One B-rep face of a CAD part: STEP entity #1081.
In plain terms, the planar face has unit normal (0, -1, 0).
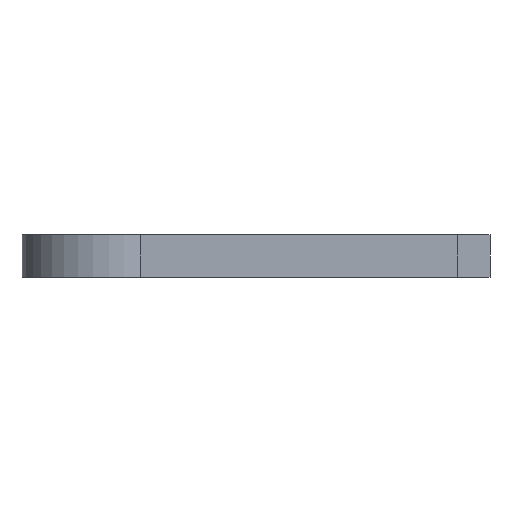
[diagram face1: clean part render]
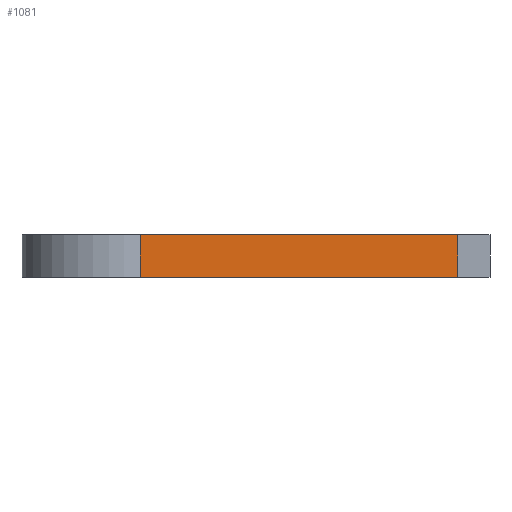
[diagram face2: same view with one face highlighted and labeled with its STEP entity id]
Its self-contained STEP definition (entity closure, numbers rounded to 3 decimals):
#42 = VERTEX_POINT('',#43);
#43 = CARTESIAN_POINT('',(65.8,-85.5,9.6));
#50 = PLANE('',#51);
#51 = AXIS2_PLACEMENT_3D('',#52,#53,#54);
#52 = CARTESIAN_POINT('',(65.8,-100.2,4.8));
#53 = DIRECTION('',(1.,0.,0.));
#54 = DIRECTION('',(0.,0.,1.));
#62 = PLANE('',#63);
#63 = AXIS2_PLACEMENT_3D('',#64,#65,#66);
#64 = CARTESIAN_POINT('',(65.8,-100.2,9.6));
#65 = DIRECTION('',(0.,0.,1.));
#66 = DIRECTION('',(1.,0.,-0.));
#272 = VERTEX_POINT('',#273);
#273 = CARTESIAN_POINT('',(65.8,-85.5,57.292));
#288 = CYLINDRICAL_SURFACE('',#289,14.);
#289 = AXIS2_PLACEMENT_3D('',#290,#291,#292);
#290 = CARTESIAN_POINT('',(65.8,-72.,61.));
#291 = DIRECTION('',(1.,0.,0.));
#292 = DIRECTION('',(0.,0.,-1.));
#300 = EDGE_CURVE('',#42,#272,#301,.T.);
#301 = SURFACE_CURVE('',#302,(#306,#313),.PCURVE_S1.);
#302 = LINE('',#303,#304);
#303 = CARTESIAN_POINT('',(65.8,-85.5,9.6));
#304 = VECTOR('',#305,1.);
#305 = DIRECTION('',(0.,0.,1.));
#306 = PCURVE('',#50,#307);
#307 = DEFINITIONAL_REPRESENTATION('',(#308),#312);
#308 = LINE('',#309,#310);
#309 = CARTESIAN_POINT('',(4.8,-14.7));
#310 = VECTOR('',#311,1.);
#311 = DIRECTION('',(1.,0.));
#312 = ( GEOMETRIC_REPRESENTATION_CONTEXT(2) 
PARAMETRIC_REPRESENTATION_CONTEXT() REPRESENTATION_CONTEXT('2D SPACE',''
  ) );
#313 = PCURVE('',#314,#319);
#314 = PLANE('',#315);
#315 = AXIS2_PLACEMENT_3D('',#316,#317,#318);
#316 = CARTESIAN_POINT('',(65.8,-85.5,9.6));
#317 = DIRECTION('',(0.,1.,0.));
#318 = DIRECTION('',(0.,-0.,1.));
#319 = DEFINITIONAL_REPRESENTATION('',(#320),#324);
#320 = LINE('',#321,#322);
#321 = CARTESIAN_POINT('',(0.,0.));
#322 = VECTOR('',#323,1.);
#323 = DIRECTION('',(1.,0.));
#324 = ( GEOMETRIC_REPRESENTATION_CONTEXT(2) 
PARAMETRIC_REPRESENTATION_CONTEXT() REPRESENTATION_CONTEXT('2D SPACE',''
  ) );
#530 = VERTEX_POINT('',#531);
#531 = CARTESIAN_POINT('',(72.2,-85.5,9.6));
#545 = PLANE('',#546);
#546 = AXIS2_PLACEMENT_3D('',#547,#548,#549);
#547 = CARTESIAN_POINT('',(72.2,-100.2,4.8));
#548 = DIRECTION('',(1.,0.,0.));
#549 = DIRECTION('',(0.,0.,1.));
#557 = EDGE_CURVE('',#42,#530,#558,.T.);
#558 = SURFACE_CURVE('',#559,(#563,#570),.PCURVE_S1.);
#559 = LINE('',#560,#561);
#560 = CARTESIAN_POINT('',(65.8,-85.5,9.6));
#561 = VECTOR('',#562,1.);
#562 = DIRECTION('',(1.,0.,0.));
#563 = PCURVE('',#62,#564);
#564 = DEFINITIONAL_REPRESENTATION('',(#565),#569);
#565 = LINE('',#566,#567);
#566 = CARTESIAN_POINT('',(0.,14.7));
#567 = VECTOR('',#568,1.);
#568 = DIRECTION('',(1.,0.));
#569 = ( GEOMETRIC_REPRESENTATION_CONTEXT(2) 
PARAMETRIC_REPRESENTATION_CONTEXT() REPRESENTATION_CONTEXT('2D SPACE',''
  ) );
#570 = PCURVE('',#314,#571);
#571 = DEFINITIONAL_REPRESENTATION('',(#572),#576);
#572 = LINE('',#573,#574);
#573 = CARTESIAN_POINT('',(0.,0.));
#574 = VECTOR('',#575,1.);
#575 = DIRECTION('',(0.,1.));
#576 = ( GEOMETRIC_REPRESENTATION_CONTEXT(2) 
PARAMETRIC_REPRESENTATION_CONTEXT() REPRESENTATION_CONTEXT('2D SPACE',''
  ) );
#1037 = VERTEX_POINT('',#1038);
#1038 = CARTESIAN_POINT('',(72.2,-85.5,57.292));
#1062 = EDGE_CURVE('',#272,#1037,#1063,.T.);
#1063 = SURFACE_CURVE('',#1064,(#1068,#1074),.PCURVE_S1.);
#1064 = LINE('',#1065,#1066);
#1065 = CARTESIAN_POINT('',(65.8,-85.5,57.292));
#1066 = VECTOR('',#1067,1.);
#1067 = DIRECTION('',(1.,0.,0.));
#1068 = PCURVE('',#288,#1069);
#1069 = DEFINITIONAL_REPRESENTATION('',(#1070),#1073);
#1070 = B_SPLINE_CURVE_WITH_KNOTS('',1,(#1071,#1072),.UNSPECIFIED.,.F.,
  .F.,(2,2),(0.,6.4),.PIECEWISE_BEZIER_KNOTS.);
#1071 = CARTESIAN_POINT('',(4.98,0.));
#1072 = CARTESIAN_POINT('',(4.98,6.4));
#1073 = ( GEOMETRIC_REPRESENTATION_CONTEXT(2) 
PARAMETRIC_REPRESENTATION_CONTEXT() REPRESENTATION_CONTEXT('2D SPACE',''
  ) );
#1074 = PCURVE('',#314,#1075);
#1075 = DEFINITIONAL_REPRESENTATION('',(#1076),#1080);
#1076 = LINE('',#1077,#1078);
#1077 = CARTESIAN_POINT('',(47.692,0.));
#1078 = VECTOR('',#1079,1.);
#1079 = DIRECTION('',(0.,1.));
#1080 = ( GEOMETRIC_REPRESENTATION_CONTEXT(2) 
PARAMETRIC_REPRESENTATION_CONTEXT() REPRESENTATION_CONTEXT('2D SPACE',''
  ) );
#1081 = ADVANCED_FACE('',(#1082),#314,.F.);
#1082 = FACE_BOUND('',#1083,.F.);
#1083 = EDGE_LOOP('',(#1084,#1105,#1106,#1107));
#1084 = ORIENTED_EDGE('',*,*,#1085,.F.);
#1085 = EDGE_CURVE('',#530,#1037,#1086,.T.);
#1086 = SURFACE_CURVE('',#1087,(#1091,#1098),.PCURVE_S1.);
#1087 = LINE('',#1088,#1089);
#1088 = CARTESIAN_POINT('',(72.2,-85.5,9.6));
#1089 = VECTOR('',#1090,1.);
#1090 = DIRECTION('',(0.,0.,1.));
#1091 = PCURVE('',#314,#1092);
#1092 = DEFINITIONAL_REPRESENTATION('',(#1093),#1097);
#1093 = LINE('',#1094,#1095);
#1094 = CARTESIAN_POINT('',(0.,6.4));
#1095 = VECTOR('',#1096,1.);
#1096 = DIRECTION('',(1.,0.));
#1097 = ( GEOMETRIC_REPRESENTATION_CONTEXT(2) 
PARAMETRIC_REPRESENTATION_CONTEXT() REPRESENTATION_CONTEXT('2D SPACE',''
  ) );
#1098 = PCURVE('',#545,#1099);
#1099 = DEFINITIONAL_REPRESENTATION('',(#1100),#1104);
#1100 = LINE('',#1101,#1102);
#1101 = CARTESIAN_POINT('',(4.8,-14.7));
#1102 = VECTOR('',#1103,1.);
#1103 = DIRECTION('',(1.,0.));
#1104 = ( GEOMETRIC_REPRESENTATION_CONTEXT(2) 
PARAMETRIC_REPRESENTATION_CONTEXT() REPRESENTATION_CONTEXT('2D SPACE',''
  ) );
#1105 = ORIENTED_EDGE('',*,*,#557,.F.);
#1106 = ORIENTED_EDGE('',*,*,#300,.T.);
#1107 = ORIENTED_EDGE('',*,*,#1062,.T.);
